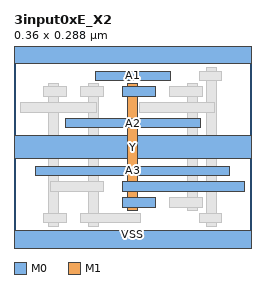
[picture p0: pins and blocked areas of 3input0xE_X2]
MACRO 3input0xE_X2
  CLASS CORE ;
  ORIGIN 0 0 ;
  FOREIGN 3input0xE_X2 0 0 ;
  SIZE 0.3600 BY 0.2880 ;
  SYMMETRY X Y ;
  SITE coresite ;
  PIN A1
    DIRECTION INPUT ;
    USE SIGNAL ;
    PORT
      LAYER M0 ;
        RECT 0.1230 0.2450 0.2370 0.2590 ;
    END
  END A1
  PIN A2
    DIRECTION INPUT ;
    USE SIGNAL ;
    PORT
      LAYER M0 ;
        RECT 0.0780 0.1730 0.2820 0.1870 ;
    END
  END A2
  PIN A3
    DIRECTION INPUT ;
    USE SIGNAL ;
    PORT
      LAYER M0 ;
        RECT 0.0330 0.1010 0.3270 0.1150 ;
    END
  END A3
  PIN Y
    DIRECTION OUTPUT ;
    USE SIGNAL ;
    PORT
      LAYER M1 ;
        RECT 0.1725 0.0480 0.1875 0.2400 ;
      LAYER M0 ;
        RECT 0.1650 0.0770 0.3495 0.0910 ;
        RECT 0.1650 0.0530 0.2145 0.0670 ;
        RECT 0.1650 0.2210 0.2145 0.2350 ;
    END
  END Y
  PIN VDD
    DIRECTION INOUT ;
    USE POWER ;
    SHAPE ABUTMENT ;
    PORT
      LAYER M0 ;
        RECT 0.0000 0.1260 0.3600 0.1620 ;
    END
  END VDD
  PIN VSS
    DIRECTION INOUT ;
    USE GROUND ;
    SHAPE ABUTMENT ;
    PORT
      LAYER M0 ;
        RECT 0.0000 0.2700 0.3600 0.3060 ;
        RECT 0.0000 -0.0180 0.3600 0.0180 ;
    END
  END VSS
  OBS
    LAYER M1 ;
      RECT 0.0525 0.0240 0.0675 0.2400 ;
      RECT 0.1125 0.0240 0.1275 0.2400 ;
      RECT 0.2625 0.0480 0.2775 0.2400 ;
      RECT 0.2925 0.0240 0.3075 0.2640 ;
    LAYER V0 ;
      RECT 0.1730 0.0770 0.1870 0.0910 ;
      RECT 0.1730 0.0530 0.1870 0.0670 ;
      RECT 0.1730 0.2210 0.1870 0.2350 ;
      RECT 0.1130 0.0770 0.1270 0.0910 ;
      RECT 0.1130 0.0290 0.1270 0.0430 ;
      RECT 0.1130 0.2210 0.1270 0.2350 ;
      RECT 0.0530 0.0290 0.0670 0.0430 ;
      RECT 0.0530 0.2210 0.0670 0.2350 ;
      RECT 0.2930 0.0290 0.3070 0.0430 ;
      RECT 0.2930 0.2450 0.3070 0.2590 ;
      RECT 0.2630 0.0530 0.2770 0.0670 ;
      RECT 0.2630 0.2210 0.2770 0.2350 ;
    LAYER M0 ;
      RECT 0.0450 0.0290 0.0795 0.0430 ;
      RECT 0.1005 0.0290 0.1920 0.0430 ;
      RECT 0.2805 0.0290 0.3150 0.0430 ;
      RECT 0.2355 0.0530 0.2850 0.0670 ;
      RECT 0.0555 0.0770 0.1350 0.0910 ;
      RECT 0.0105 0.1970 0.1245 0.2110 ;
      RECT 0.1905 0.1970 0.3045 0.2110 ;
      RECT 0.0450 0.2210 0.0795 0.2350 ;
      RECT 0.1005 0.2210 0.1350 0.2350 ;
      RECT 0.2355 0.2210 0.2850 0.2350 ;
      RECT 0.2805 0.2450 0.3150 0.2590 ;
  END
END 3input0xE_X2
